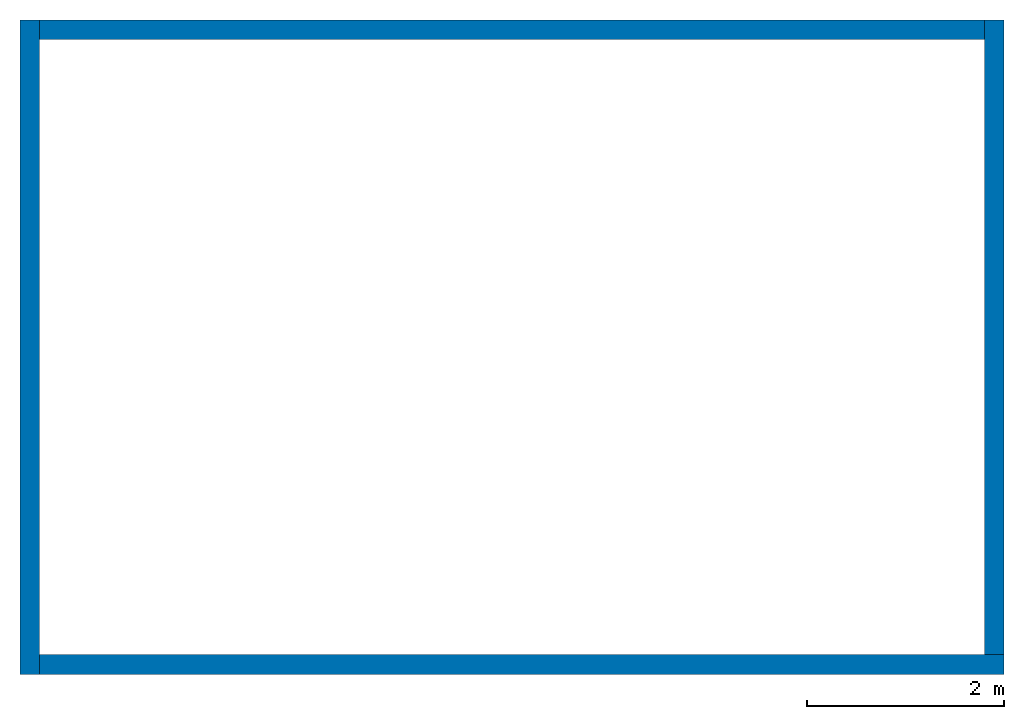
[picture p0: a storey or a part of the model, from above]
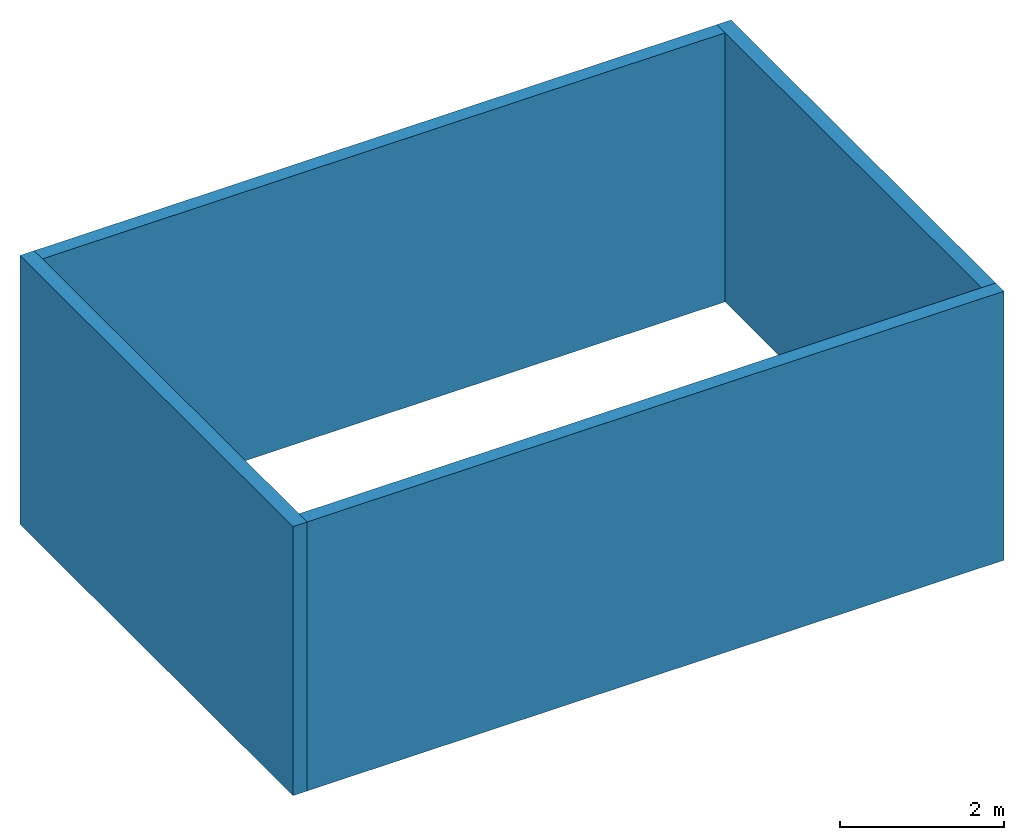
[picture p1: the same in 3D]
Properties of the parts of a building model (IFC2X3)

# File
Description: ViewDefinition [CoordinationView_V2.0, QuantityTakeOffAddOnView]
Time: 2021-03-05T10:46:27
Written by: The EXPRESS Data Manager Version 5.02.0100.07 : 28 Aug 2013
Made in: 21.1.20.44 - Exporter 21.2.1.0 - Alternate UI 21.2.1.0
Comment: STEP Physical File produced by: The EXPRESS Data Manager Version 5.02.0100.07 : 28 Aug 2013 * Module: EDMstepFileFactory/EDMstandAlone * Creation date: Fri Mar 05 10:46:27 2021 * Host: VASP10 * Database: C:\Users\G1E01~1.VAN\AppData\Local\Temp\4\f9211231-cbed-4c6a-9bf8-afacf131fa78\218fe239-fddc-48e9-a5b4-ba68d1625e6c\ifc * Database version: 5507 * Database creation date: Fri Mar 05 10:46:26 2021 * Schema: IFC2X3 * Model: DataRepository.ifc * Model creation date: Fri Mar 05 10:46:27 2021 * Header model: DataRepository.ifc_HeaderModel * Header model creation date: Fri Mar 05 10:46:27 2021 * EDMuser: sdai-user * EDMgroup: sdai-group * License ID and type: 5605 : Permanent license. Expiry date: * EDMstepFileFactory options: 020000

# IfcSite, Default
RefLatitude: 42, 24, 53, 508911; RefLongitude: -71, -15, -29, -58837; RefElevation: 0 mm
Pset_ProductRequirements - Category: Project Information; sets with these values: 2

# IfcBuilding
Pset_BuildingCommon - NumberOfStoreys: 1
Pset_ProductRequirements - Category: Project Information; sets with these values: 2

# IfcBuildingStorey: Level:Level 1 (2)
Pset_ProductRequirements - Category: Levels
Dimensions - Computation Height: 0 mm
Identity Data - Structural: no; Building Story: yes
Other - Category: Levels; Family: Level: Level 1; Family and Type: Level: Level 1; Type: Level: Level 1; Type Id: Level: Level 1
Constraints(Type) - Elevation Base: Project Base Point
Graphics(Type) - Color: 0; Line Pattern: Solid; Line Weight: 1; Symbol at End 1 Default: no; Symbol at End 2 Default: yes
Identity Data(Type) - Type Name: Level 1
Other(Type) - Category: Levels; Family Name: Level
Name | LongName = Pset_AirSideSystemInformation, Name = Pset_ProductRequirements, Name = Identity Data, Name | Elevation (mm) = Constraints, Elevation (mm)
Level 1 | Level 1 | 0
Level 2 | Level 2 | 4000

# IfcSpace: Area:10563
In: Level 1
LongName: Hal; InteriorOrExteriorSpace: INTERNAL; Group: Brutovloeroppervlakte
Pset_AirSideSystemInformation - Name: Hal; sets with these values: 2
Pset_ProductRequirements - Name: Hal; Category: Areas
Pset_SpaceCommon - Reference: Area; Category: Areas
BaseQuantities - NetFloorArea: 129.69 m2; Height: 4000 mm; GrossPerimeter: 150.919 mm; GrossFloorArea: 129.69 m2; GrossVolume: 518.76 m3
Constraints - Level: Level 1
Dimensions - Computation Height: 0 mm; Area: 129.69 m2; Perimeter: 46000 mm
Other - Area Scheme Id: Brutovloeroppervlakte; Area Type: Building Common Area; Category: Areas

# IfcSpace: Area:10566
In: Level 1
LongName: Kantoor; InteriorOrExteriorSpace: INTERNAL; Group: Brutovloeroppervlakte
Pset_AirSideSystemInformation - Name: Kantoor; sets with these values: 2
Pset_ProductRequirements - Name: Kantoor; Category: Areas
Pset_SpaceCommon - Reference: Area; Category: Areas
BaseQuantities - NetFloorArea: 129.69 m2; Height: 4000 mm; GrossPerimeter: 150.919 mm; GrossFloorArea: 129.69 m2; GrossVolume: 518.76 m3
Constraints - Level: Level 1
Dimensions - Computation Height: 0 mm; Area: 129.69 m2; Perimeter: 46000 mm
Other - Area Scheme Id: Brutovloeroppervlakte; Category: Areas; Area Type: Building Common Area

# IfcSpace: Area:10864
In: Level 2
LongName: Kantoor; InteriorOrExteriorSpace: INTERNAL; Group: Brutovloeroppervlakte
Pset_AirSideSystemInformation - Name: Kantoor; sets with these values: 2
Pset_ProductRequirements - Name: Kantoor; Category: Areas
Pset_SpaceCommon - Reference: Area; Category: Areas
BaseQuantities - NetFloorArea: 129.69 m2; Height: 1 mm; GrossPerimeter: 150.919 mm; GrossFloorArea: 129.69 m2; GrossVolume: 0.12969 m3
Constraints - Level: Level 2
Dimensions - Computation Height: 0 mm; Area: 129.69 m2; Perimeter: 46000 mm
Other - Area Scheme Id: Brutovloeroppervlakte; Category: Areas; Area Type: Building Common Area

# IfcSpace: Area:10867
In: Level 2
LongName: Hal; InteriorOrExteriorSpace: INTERNAL; Group: Brutovloeroppervlakte
Pset_AirSideSystemInformation - Name: Hal; sets with these values: 2
Pset_ProductRequirements - Name: Hal; Category: Areas
Pset_SpaceCommon - Reference: Area; Category: Areas
BaseQuantities - NetFloorArea: 129.69 m2; Height: 1 mm; GrossPerimeter: 150.919 mm; GrossFloorArea: 129.69 m2; GrossVolume: 0.12969 m3
Constraints - Level: Level 2
Dimensions - Computation Height: 0 mm; Area: 129.69 m2; Perimeter: 46000 mm
Other - Area Scheme Id: Brutovloeroppervlakte; Category: Areas; Area Type: Building Common Area

# IfcSpace: Name
In: Level 1
LongName: Longname; InteriorOrExteriorSpace: INTERNAL
Pset_AirSideSystemInformation - Name: Room
Pset_ProductRequirements - Name: Room; Category: Rooms
Pset_SpaceCommon - Reference: Room 4; Category: Rooms
BaseQuantities - NetFloorArea: 60 m2; Height: 2600 mm; GrossPerimeter: 104.003 mm; GrossFloorArea: 60 m2; GrossVolume: 156 m3
Constraints - Base Offset: 0 mm; Level: Level 1; Limit Offset: 2600 mm; Upper Limit: Level: Level 1
Dimensions - Area: 60 m2; Computation Height: 0 mm; Perimeter: 31700 mm; Unbounded Height: 2600 mm
Energy Analysis - Actual Lighting Load: 0 W; Actual Lighting Load per area: 0; Actual Power Load: 0 W; Actual Power Load per area: 0; Area per Person: 28.5714 m2; Base Lighting Load on: By Space Type; Base Power Load on: By Space Type; Heat Load Values: By Space Type; Latent Heat Gain per person: 58.6142 W; Lighting Load Units: Power Density; Number of People: 0; Plenum Lighting Contribution: 20; Power Load Units: Power Density; Sensible Heat Gain per person: 73.2678 W; Specified Lighting Load: 0 W; Specified Lighting Load per area: 10.7639; Specified Power Load: 0 W; Specified Power Load per area: 13.9931; Total Heat Gain per person: 131.882 W
Identity Data - IfcLongName: Longname; IfcName: Name; IfcObjectType: Test3; IfcObjectTypeOverride: Test2; Name: Room; Number: 4; ObjectTypeOverride: Test
Other - Category: Rooms; Phase Id: New Construction
Phasing - Phase: New Construction

# IfcGroup, Brutovloeroppervlakte
Other - Category: Area Schemes; Name: Brutovloeroppervlakte

# IfcWallStandardCase: Basic Wall:Wall 1 (4)
In: Level 1
Type - PredefinedType: STANDARD; Material: Default Wall 200 mm
Type - Analytical Properties - Absorptance: 0.1; Roughness: 1
Type - Construction - Function: Exterior; Width: 200 mm; Wrapping at Inserts: Do not wrap
Type - Graphics - Coarse Scale Fill Color: 0
Type - Identity Data - Type Name: Wall 1
Type - Other - Category: Walls; Family Name: Basic Wall
Type - Pset_ElementShading - Roughness: 304.8 mm
Type - Pset_ProductRequirements - Category: Walls
Type - Pset_WallCommon - IsExternal: yes
BaseQuantities - Height: 4000 mm; Width: 200 mm
Constraints - Base Offset: 0 mm; Base Constraint: Level: Level 1; Base Extension Distance: 0 mm; Base is Attached: no; Cross-Section: Vertical; Location Line: Wall Centerline; Related to Mass: no; Room Bounding: yes; Top Extension Distance: 0 mm; Top is Attached: no; Top Offset: 0 mm; Unconnected Height: 4000 mm
Other - Family: Basic Wall: Wall 1; Family and Type: Basic Wall: Wall 1; Type: Basic Wall: Wall 1; Type Id: Basic Wall: Wall 1
Phasing - Phase Created: New Construction
Structural - Enable Analytical Model: no; Structural: no; Structural Usage: Non-bearing
Pset_QuantityTakeOff - Reference: Wall 1; sets with these values: 2
Pset_WallCommon - Reference: Wall 1; ExtendToStructure: no; LoadBearing: no
Name | BaseQuantities, Length (mm) | GrossFootprintArea (m2) | GrossVolume (m3) = NetVolume (m3) = Volume (m3) | GrossSideArea (m2) = NetSideArea (m2) = Area (m2) | Dimensions, Length (mm)
Basic Wall:Wall 1:9856 | 6650 | 1.33 | 5.32 | 26.6 | 6450
Name | 9800 | 1.96 | 7.84 | 39.2 | 9800 | Identity Data - IfcLongName: Long; IfcName: Name; ObjectTypeOverride: test
Basic Wall:Wall 1:9894 | 6450 | 1.29 | 5.16 | 25.8 | 6450
Basic Wall:Wall 1:9921 | 9600 | 1.92 | 7.68 | 38.4 | 9800
